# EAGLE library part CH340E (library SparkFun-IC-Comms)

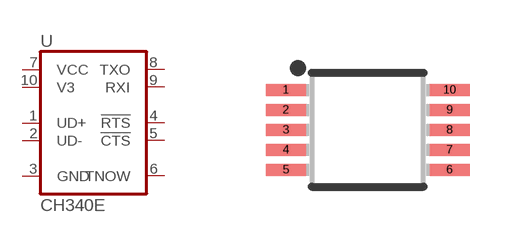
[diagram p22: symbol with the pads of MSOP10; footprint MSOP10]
Designator prefix U

## CH340E_MSOP10 (PROD_ID: IC-14135)  [MSOP10]
1  UD+
2  UD-
3  GND
4  !RTS
5  !CTS
6  TNOW
7  VCC
8  TXO
9  RXI
10  V3

## Footprint MSOP10 (pad centres in mm)
smd 1 x 0.3: 1 -2.05,1; 2 -2.05,0.5; 3 -2.05,0; 4 -2.05,-0.5; 5 -2.05,-1; 6 2.05,-1; 7 2.05,-0.5; 8 2.05,0; 9 2.05,0.5; 10 2.05,1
